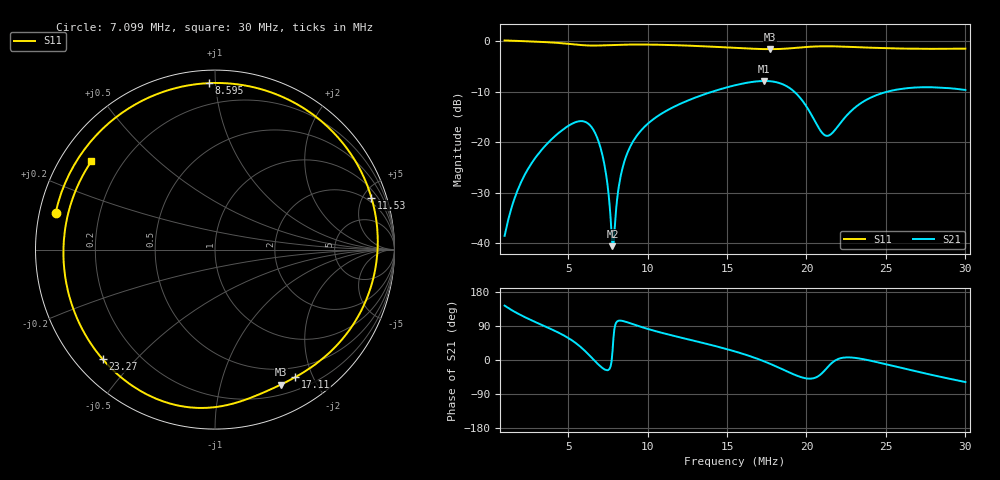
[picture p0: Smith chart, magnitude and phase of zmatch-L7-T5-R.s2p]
# HZ S RI R 50
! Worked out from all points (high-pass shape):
!   505 points, 1 MHz to 30 MHz, reference 50 ohm
!   highest |S21| = -7.85 dB at 17.34 MHz (marker M1); lowest = -40.6 dB at 7.79 MHz (marker M2)
!   |S21| within 3 dB of the highest: 13.25 MHz to 19.51 MHz (6.256 MHz wide, 38.2 % of centre); 24.25 MHz to end of sweep
!   lowest |S11| = -1.5 dB at 17.69 MHz (marker M3), VSWR 11.27, Z = 15.5 - j77.8 ohm
!   |S11| at or under -10 dB: nowhere
!   S12 and S22 are empty: the file has one direction only
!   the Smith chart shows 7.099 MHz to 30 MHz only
!   S11 on the Smith chart (normalised r, x): 7.099 MHz: 0.05, +0.11; 8.595 MHz: 0.07, +0.96; 11.53 MHz: 1.56, +5.78; 17.11 MHz: 0.36, -1.76; 23.27 MHz: 0.08, -0.40; 30 MHz: 0.09, +0.32
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1000000  -0.6391 0.7954  -0.00952 0.00705  0 0  0 0
2438500  0.3041 0.9535  -0.018 0.0502  0 0  0 0
3992080  0.9616 0.1527  0.0184 0.1069  0 0  0 0
4912720  0.7451 -0.5868  0.0702 0.1237  0 0  0 0
5430580  0.3034 -0.8803  0.1089 0.1137  0 0  0 0
5833360  -0.1556 -0.9053  0.1365 0.0875  0 0  0 0
6523840  -0.8035 -0.4229  0.1375 0.01  0 0  0 0
7099240  -0.8881 0.2051  0.0766 -0.0267  0 0  0 0
7444480  -0.7567 0.5163  0.037 -0.0188  0 0  0 0
7789720  -0.5542 0.7352  0.00866 0.00352  0 0  0 0
8595280  -0.0341 0.9274  -0.0135 0.0676  0 0  0 0
1.066672e7  0.7578 0.5312  0.0497 0.1763  0 0  0 0
1.152982e7  0.8716 0.2893  0.093 0.1988  0 0  0 0
1.550008e7  0.6693 -0.5431  0.339 0.1409  0 0  0 0
1.71112e7  0.448 -0.7103  0.4038 0.000328  0 0  0 0
1.734136e7  0.4155 -0.7279  0.404 -0.0263  0 0  0 0
1.76866e7  0.3668 -0.7523  0.3972 -0.0675  0 0  0 0
2.033344e7  -0.0836 -0.8822  0.1211 -0.1389  0 0  0 0
2.136916e7  -0.3047 -0.8399  0.111 -0.0341  0 0  0 0
2.326798e7  -0.6267 -0.6099  0.234 0.0179  0 0  0 0
2.51668e7  -0.8023 -0.2921  0.3116 -0.0708  0 0  0 0
3.000016e7  -0.6882 0.493  0.1745 -0.2803  0 0  0 0
